VERSION 5.7 ;
  NOWIREEXTENSIONATPIN ON ;
  DIVIDERCHAR "/" ;
  BUSBITCHARS "[]" ;
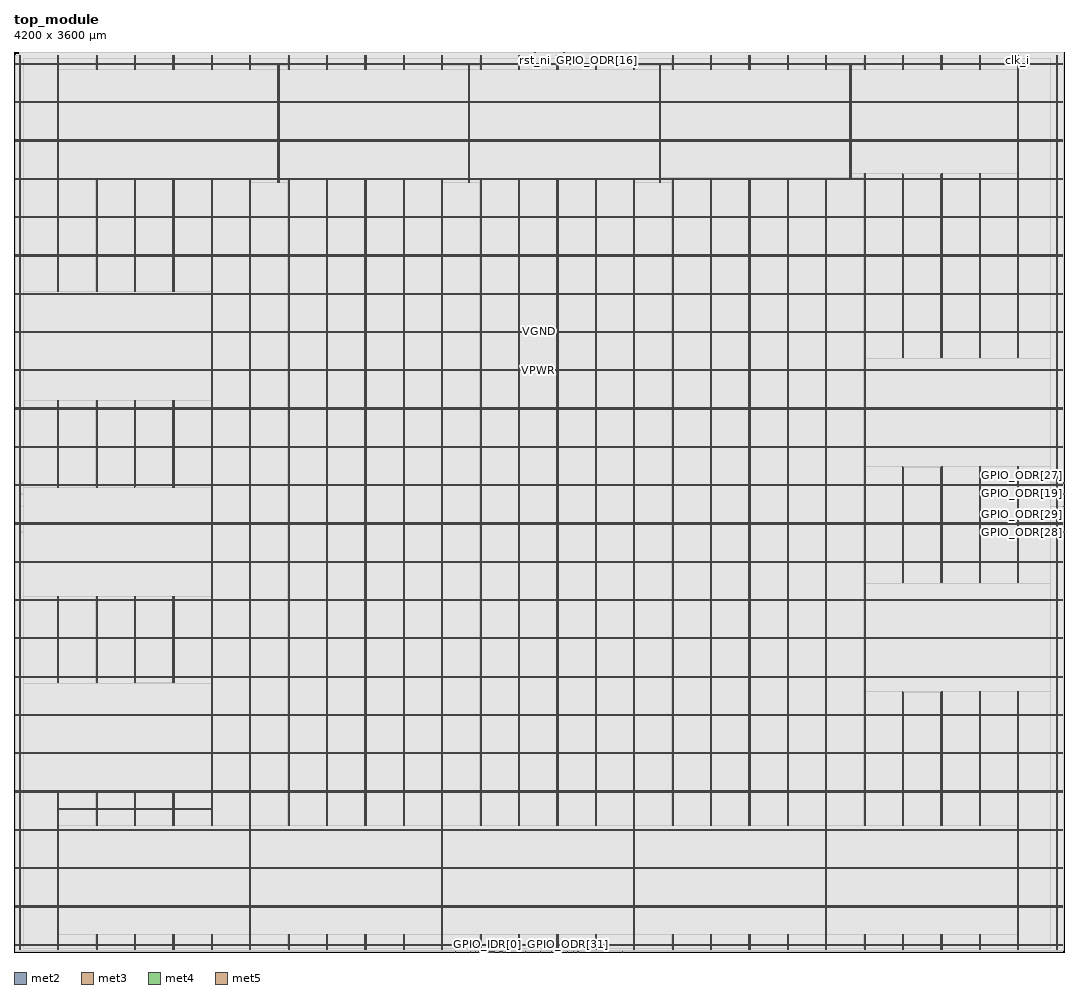
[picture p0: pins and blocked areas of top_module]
MACRO top_module
  CLASS BLOCK ;
  FOREIGN top_module ;
  ORIGIN 0.000 0.000 ;
  SIZE 4200.000 BY 3600.000 ;
  PIN GPIO_IDR[0]
    DIRECTION INPUT ;
    USE SIGNAL ;
    ANTENNAGATEAREA 0.126000 ;
    PORT
      LAYER met2 ;
        RECT 1895.290 0.000 1895.570 0.280 ;
    END
  END GPIO_IDR[0]
  PIN GPIO_IDR[10]
    DIRECTION INPUT ;
    USE SIGNAL ;
    ANTENNAGATEAREA 0.126000 ;
    PORT
      LAYER met2 ;
        RECT 1898.970 0.000 1899.250 0.280 ;
    END
  END GPIO_IDR[10]
  PIN GPIO_IDR[11]
    DIRECTION INPUT ;
    USE SIGNAL ;
    ANTENNAGATEAREA 0.126000 ;
    PORT
      LAYER met2 ;
        RECT 1899.890 0.000 1900.170 0.280 ;
    END
  END GPIO_IDR[11]
  PIN GPIO_IDR[12]
    DIRECTION INPUT ;
    USE SIGNAL ;
    ANTENNAGATEAREA 0.126000 ;
    PORT
      LAYER met2 ;
        RECT 1915.530 0.000 1915.810 0.280 ;
    END
  END GPIO_IDR[12]
  PIN GPIO_IDR[13]
    DIRECTION INPUT ;
    USE SIGNAL ;
    ANTENNAGATEAREA 0.126000 ;
    PORT
      LAYER met2 ;
        RECT 1914.610 0.000 1914.890 0.280 ;
    END
  END GPIO_IDR[13]
  PIN GPIO_IDR[14]
    DIRECTION INPUT ;
    USE SIGNAL ;
    ANTENNAGATEAREA 0.126000 ;
    PORT
      LAYER met2 ;
        RECT 1916.450 0.000 1916.730 0.280 ;
    END
  END GPIO_IDR[14]
  PIN GPIO_IDR[15]
    DIRECTION INPUT ;
    USE SIGNAL ;
    ANTENNAGATEAREA 0.126000 ;
    PORT
      LAYER met2 ;
        RECT 1913.690 0.000 1913.970 0.280 ;
    END
  END GPIO_IDR[15]
  PIN GPIO_IDR[16]
    DIRECTION INPUT ;
    USE SIGNAL ;
    ANTENNAGATEAREA 0.126000 ;
    PORT
      LAYER met2 ;
        RECT 1950.490 0.000 1950.770 0.280 ;
    END
  END GPIO_IDR[16]
  PIN GPIO_IDR[17]
    DIRECTION INPUT ;
    USE SIGNAL ;
    ANTENNAGATEAREA 0.126000 ;
    PORT
      LAYER met2 ;
        RECT 1949.570 0.000 1949.850 0.280 ;
    END
  END GPIO_IDR[17]
  PIN GPIO_IDR[18]
    DIRECTION INPUT ;
    USE SIGNAL ;
    ANTENNAGATEAREA 0.126000 ;
    PORT
      LAYER met2 ;
        RECT 1945.890 0.000 1946.170 0.280 ;
    END
  END GPIO_IDR[18]
  PIN GPIO_IDR[19]
    DIRECTION INPUT ;
    USE SIGNAL ;
    ANTENNAGATEAREA 0.126000 ;
    PORT
      LAYER met2 ;
        RECT 1946.810 0.000 1947.090 0.280 ;
    END
  END GPIO_IDR[19]
  PIN GPIO_IDR[1]
    DIRECTION INPUT ;
    USE SIGNAL ;
    ANTENNAGATEAREA 0.126000 ;
    PORT
      LAYER met2 ;
        RECT 1887.010 0.000 1887.290 0.280 ;
    END
  END GPIO_IDR[1]
  PIN GPIO_IDR[20]
    DIRECTION INPUT ;
    USE SIGNAL ;
    ANTENNAGATEAREA 0.126000 ;
    PORT
      LAYER met2 ;
        RECT 1966.130 0.000 1966.410 0.280 ;
    END
  END GPIO_IDR[20]
  PIN GPIO_IDR[21]
    DIRECTION INPUT ;
    USE SIGNAL ;
    ANTENNAGATEAREA 0.126000 ;
    PORT
      LAYER met2 ;
        RECT 1965.210 0.000 1965.490 0.280 ;
    END
  END GPIO_IDR[21]
  PIN GPIO_IDR[22]
    DIRECTION INPUT ;
    USE SIGNAL ;
    ANTENNAGATEAREA 0.126000 ;
    PORT
      LAYER met2 ;
        RECT 1967.050 0.000 1967.330 0.280 ;
    END
  END GPIO_IDR[22]
  PIN GPIO_IDR[23]
    DIRECTION INPUT ;
    USE SIGNAL ;
    ANTENNAGATEAREA 0.126000 ;
    PORT
      LAYER met2 ;
        RECT 1964.290 0.000 1964.570 0.280 ;
    END
  END GPIO_IDR[23]
  PIN GPIO_IDR[24]
    DIRECTION INPUT ;
    USE SIGNAL ;
    ANTENNAGATEAREA 0.126000 ;
    PORT
      LAYER met2 ;
        RECT 1942.210 0.000 1942.490 0.280 ;
    END
  END GPIO_IDR[24]
  PIN GPIO_IDR[25]
    DIRECTION INPUT ;
    USE SIGNAL ;
    ANTENNAGATEAREA 0.126000 ;
    PORT
      LAYER met2 ;
        RECT 1952.330 0.000 1952.610 0.280 ;
    END
  END GPIO_IDR[25]
  PIN GPIO_IDR[26]
    DIRECTION INPUT ;
    USE SIGNAL ;
    ANTENNAGATEAREA 0.126000 ;
    PORT
      LAYER met2 ;
        RECT 1944.970 0.000 1945.250 0.280 ;
    END
  END GPIO_IDR[26]
  PIN GPIO_IDR[27]
    DIRECTION INPUT ;
    USE SIGNAL ;
    ANTENNAGATEAREA 0.126000 ;
    PORT
      LAYER met2 ;
        RECT 1951.410 0.000 1951.690 0.280 ;
    END
  END GPIO_IDR[27]
  PIN GPIO_IDR[28]
    DIRECTION INPUT ;
    USE SIGNAL ;
    ANTENNAGATEAREA 0.126000 ;
    PORT
      LAYER met2 ;
        RECT 1921.970 0.000 1922.250 0.280 ;
    END
  END GPIO_IDR[28]
  PIN GPIO_IDR[29]
    DIRECTION INPUT ;
    USE SIGNAL ;
    ANTENNAGATEAREA 0.126000 ;
    PORT
      LAYER met2 ;
        RECT 1921.050 0.000 1921.330 0.280 ;
    END
  END GPIO_IDR[29]
  PIN GPIO_IDR[2]
    DIRECTION INPUT ;
    USE SIGNAL ;
    ANTENNAGATEAREA 0.126000 ;
    PORT
      LAYER met2 ;
        RECT 1886.090 0.000 1886.370 0.280 ;
    END
  END GPIO_IDR[2]
  PIN GPIO_IDR[30]
    DIRECTION INPUT ;
    USE SIGNAL ;
    ANTENNAGATEAREA 0.126000 ;
    PORT
      LAYER met2 ;
        RECT 1880.570 0.000 1880.850 0.280 ;
    END
  END GPIO_IDR[30]
  PIN GPIO_IDR[31]
    DIRECTION INPUT ;
    USE SIGNAL ;
    ANTENNAGATEAREA 0.126000 ;
    PORT
      LAYER met2 ;
        RECT 1917.370 0.000 1917.650 0.280 ;
    END
  END GPIO_IDR[31]
  PIN GPIO_IDR[3]
    DIRECTION INPUT ;
    USE SIGNAL ;
    ANTENNAGATEAREA 0.126000 ;
    PORT
      LAYER met2 ;
        RECT 1885.170 0.000 1885.450 0.280 ;
    END
  END GPIO_IDR[3]
  PIN GPIO_IDR[4]
    DIRECTION INPUT ;
    USE SIGNAL ;
    ANTENNAGATEAREA 0.126000 ;
    PORT
      LAYER met2 ;
        RECT 1870.450 0.000 1870.730 0.280 ;
    END
  END GPIO_IDR[4]
  PIN GPIO_IDR[5]
    DIRECTION INPUT ;
    USE SIGNAL ;
    ANTENNAGATEAREA 0.126000 ;
    PORT
      LAYER met2 ;
        RECT 1875.970 0.000 1876.250 0.280 ;
    END
  END GPIO_IDR[5]
  PIN GPIO_IDR[6]
    DIRECTION INPUT ;
    USE SIGNAL ;
    ANTENNAGATEAREA 0.126000 ;
    PORT
      LAYER met2 ;
        RECT 1879.650 0.000 1879.930 0.280 ;
    END
  END GPIO_IDR[6]
  PIN GPIO_IDR[7]
    DIRECTION INPUT ;
    USE SIGNAL ;
    ANTENNAGATEAREA 0.126000 ;
    PORT
      LAYER met2 ;
        RECT 1878.730 0.000 1879.010 0.280 ;
    END
  END GPIO_IDR[7]
  PIN GPIO_IDR[8]
    DIRECTION INPUT ;
    USE SIGNAL ;
    ANTENNAGATEAREA 0.126000 ;
    PORT
      LAYER met2 ;
        RECT 1898.050 0.000 1898.330 0.280 ;
    END
  END GPIO_IDR[8]
  PIN GPIO_IDR[9]
    DIRECTION INPUT ;
    USE SIGNAL ;
    ANTENNAGATEAREA 0.126000 ;
    PORT
      LAYER met2 ;
        RECT 1897.130 0.000 1897.410 0.280 ;
    END
  END GPIO_IDR[9]
  PIN GPIO_ODR[0]
    DIRECTION OUTPUT ;
    USE SIGNAL ;
    ANTENNADIFFAREA 0.340600 ;
    PORT
      LAYER met2 ;
        RECT 1887.930 0.000 1888.210 0.280 ;
    END
  END GPIO_ODR[0]
  PIN GPIO_ODR[10]
    DIRECTION OUTPUT ;
    USE SIGNAL ;
    ANTENNADIFFAREA 0.340600 ;
    PORT
      LAYER met2 ;
        RECT 1900.810 0.000 1901.090 0.280 ;
    END
  END GPIO_ODR[10]
  PIN GPIO_ODR[11]
    DIRECTION OUTPUT ;
    USE SIGNAL ;
    ANTENNADIFFAREA 0.340600 ;
    PORT
      LAYER met2 ;
        RECT 1901.730 0.000 1902.010 0.280 ;
    END
  END GPIO_ODR[11]
  PIN GPIO_ODR[12]
    DIRECTION OUTPUT ;
    USE SIGNAL ;
    ANTENNADIFFAREA 0.340600 ;
    PORT
      LAYER met2 ;
        RECT 1907.250 0.000 1907.530 0.280 ;
    END
  END GPIO_ODR[12]
  PIN GPIO_ODR[13]
    DIRECTION OUTPUT ;
    USE SIGNAL ;
    ANTENNADIFFAREA 0.340600 ;
    PORT
      LAYER met2 ;
        RECT 1910.930 0.000 1911.210 0.280 ;
    END
  END GPIO_ODR[13]
  PIN GPIO_ODR[14]
    DIRECTION OUTPUT ;
    USE SIGNAL ;
    ANTENNADIFFAREA 0.340600 ;
    PORT
      LAYER met2 ;
        RECT 1912.770 0.000 1913.050 0.280 ;
    END
  END GPIO_ODR[14]
  PIN GPIO_ODR[15]
    DIRECTION OUTPUT ;
    USE SIGNAL ;
    ANTENNADIFFAREA 0.340600 ;
    PORT
      LAYER met2 ;
        RECT 1902.650 0.000 1902.930 0.280 ;
    END
  END GPIO_ODR[15]
  PIN GPIO_ODR[16]
    DIRECTION OUTPUT ;
    USE SIGNAL ;
    PORT
      LAYER met2 ;
        RECT 2333.210 3599.720 2333.490 3600.000 ;
    END
  END GPIO_ODR[16]
  PIN GPIO_ODR[17]
    DIRECTION OUTPUT ;
    USE SIGNAL ;
    PORT
      LAYER met2 ;
        RECT 2394.850 3599.720 2395.130 3600.000 ;
    END
  END GPIO_ODR[17]
  PIN GPIO_ODR[18]
    DIRECTION OUTPUT ;
    USE SIGNAL ;
    PORT
      LAYER met2 ;
        RECT 2435.330 0.000 2435.610 0.280 ;
    END
  END GPIO_ODR[18]
  PIN GPIO_ODR[19]
    DIRECTION OUTPUT ;
    USE SIGNAL ;
    PORT
      LAYER met3 ;
        RECT 4199.400 1831.960 4200.000 1832.560 ;
    END
  END GPIO_ODR[19]
  PIN GPIO_ODR[1]
    DIRECTION OUTPUT ;
    USE SIGNAL ;
    ANTENNADIFFAREA 0.340600 ;
    PORT
      LAYER met2 ;
        RECT 1888.850 0.000 1889.130 0.280 ;
    END
  END GPIO_ODR[1]
  PIN GPIO_ODR[20]
    DIRECTION OUTPUT ;
    USE SIGNAL ;
    PORT
      LAYER met2 ;
        RECT 2220.970 3599.720 2221.250 3600.000 ;
    END
  END GPIO_ODR[20]
  PIN GPIO_ODR[21]
    DIRECTION OUTPUT ;
    USE SIGNAL ;
    PORT
      LAYER met2 ;
        RECT 2192.450 3599.720 2192.730 3600.000 ;
    END
  END GPIO_ODR[21]
  PIN GPIO_ODR[22]
    DIRECTION OUTPUT ;
    USE SIGNAL ;
    PORT
      LAYER met2 ;
        RECT 2144.610 3599.720 2144.890 3600.000 ;
    END
  END GPIO_ODR[22]
  PIN GPIO_ODR[23]
    DIRECTION OUTPUT ;
    USE SIGNAL ;
    PORT
      LAYER met2 ;
        RECT 2199.810 3599.720 2200.090 3600.000 ;
    END
  END GPIO_ODR[23]
  PIN GPIO_ODR[24]
    DIRECTION OUTPUT ;
    USE SIGNAL ;
    PORT
      LAYER met2 ;
        RECT 2320.330 3599.720 2320.610 3600.000 ;
    END
  END GPIO_ODR[24]
  PIN GPIO_ODR[25]
    DIRECTION OUTPUT ;
    USE SIGNAL ;
    PORT
      LAYER met2 ;
        RECT 2295.490 3599.720 2295.770 3600.000 ;
    END
  END GPIO_ODR[25]
  PIN GPIO_ODR[26]
    DIRECTION OUTPUT ;
    USE SIGNAL ;
    PORT
      LAYER met2 ;
        RECT 2405.890 3599.720 2406.170 3600.000 ;
    END
  END GPIO_ODR[26]
  PIN GPIO_ODR[27]
    DIRECTION OUTPUT ;
    USE SIGNAL ;
    PORT
      LAYER met3 ;
        RECT 4199.400 1875.480 4200.000 1876.080 ;
    END
  END GPIO_ODR[27]
  PIN GPIO_ODR[28]
    DIRECTION OUTPUT ;
    USE SIGNAL ;
    PORT
      LAYER met3 ;
        RECT 4199.400 1679.640 4200.000 1680.240 ;
    END
  END GPIO_ODR[28]
  PIN GPIO_ODR[29]
    DIRECTION OUTPUT ;
    USE SIGNAL ;
    PORT
      LAYER met3 ;
        RECT 4199.400 1781.640 4200.000 1782.240 ;
    END
  END GPIO_ODR[29]
  PIN GPIO_ODR[2]
    DIRECTION OUTPUT ;
    USE SIGNAL ;
    ANTENNADIFFAREA 0.340600 ;
    PORT
      LAYER met2 ;
        RECT 1889.770 0.000 1890.050 0.280 ;
    END
  END GPIO_ODR[2]
  PIN GPIO_ODR[30]
    DIRECTION OUTPUT ;
    USE SIGNAL ;
    PORT
      LAYER met2 ;
        RECT 2297.330 3599.720 2297.610 3600.000 ;
    END
  END GPIO_ODR[30]
  PIN GPIO_ODR[31]
    DIRECTION OUTPUT ;
    USE SIGNAL ;
    PORT
      LAYER met2 ;
        RECT 2214.530 0.000 2214.810 0.280 ;
    END
  END GPIO_ODR[31]
  PIN GPIO_ODR[3]
    DIRECTION OUTPUT ;
    USE SIGNAL ;
    ANTENNADIFFAREA 0.340600 ;
    PORT
      LAYER met2 ;
        RECT 1882.410 0.000 1882.690 0.280 ;
    END
  END GPIO_ODR[3]
  PIN GPIO_ODR[4]
    DIRECTION OUTPUT ;
    USE SIGNAL ;
    ANTENNADIFFAREA 0.340600 ;
    PORT
      LAYER met2 ;
        RECT 1866.770 0.000 1867.050 0.280 ;
    END
  END GPIO_ODR[4]
  PIN GPIO_ODR[5]
    DIRECTION OUTPUT ;
    USE SIGNAL ;
    ANTENNADIFFAREA 0.340600 ;
    PORT
      LAYER met2 ;
        RECT 1874.130 0.000 1874.410 0.280 ;
    END
  END GPIO_ODR[5]
  PIN GPIO_ODR[6]
    DIRECTION OUTPUT ;
    USE SIGNAL ;
    ANTENNADIFFAREA 0.340600 ;
    PORT
      LAYER met2 ;
        RECT 1881.490 0.000 1881.770 0.280 ;
    END
  END GPIO_ODR[6]
  PIN GPIO_ODR[7]
    DIRECTION OUTPUT ;
    USE SIGNAL ;
    ANTENNADIFFAREA 0.340600 ;
    PORT
      LAYER met2 ;
        RECT 1891.610 0.000 1891.890 0.280 ;
    END
  END GPIO_ODR[7]
  PIN GPIO_ODR[8]
    DIRECTION OUTPUT ;
    USE SIGNAL ;
    ANTENNADIFFAREA 0.340600 ;
    PORT
      LAYER met2 ;
        RECT 1893.450 0.000 1893.730 0.280 ;
    END
  END GPIO_ODR[8]
  PIN GPIO_ODR[9]
    DIRECTION OUTPUT ;
    USE SIGNAL ;
    ANTENNADIFFAREA 0.340600 ;
    PORT
      LAYER met2 ;
        RECT 1892.530 0.000 1892.810 0.280 ;
    END
  END GPIO_ODR[9]
  PIN I2C_SCL
    DIRECTION OUTPUT ;
    USE SIGNAL ;
    ANTENNADIFFAREA 0.340600 ;
    PORT
      LAYER met2 ;
        RECT 2105.970 0.000 2106.250 0.280 ;
    END
  END I2C_SCL
  PIN I2C_SDA
    DIRECTION INOUT ;
    USE SIGNAL ;
    ANTENNAGATEAREA 0.126000 ;
    ANTENNADIFFAREA 1.782000 ;
    PORT
      LAYER met2 ;
        RECT 2046.170 0.000 2046.450 0.280 ;
    END
  END I2C_SDA
  PIN QSPI_CS
    DIRECTION OUTPUT ;
    USE SIGNAL ;
    ANTENNADIFFAREA 0.340600 ;
    PORT
      LAYER met2 ;
        RECT 2156.570 0.000 2156.850 0.280 ;
    END
  END QSPI_CS
  PIN QSPI_IO0
    DIRECTION INOUT ;
    USE SIGNAL ;
    ANTENNAGATEAREA 0.990000 ;
    ANTENNADIFFAREA 1.782000 ;
    PORT
      LAYER met2 ;
        RECT 2238.450 0.000 2238.730 0.280 ;
    END
  END QSPI_IO0
  PIN QSPI_IO1
    DIRECTION INOUT ;
    USE SIGNAL ;
    ANTENNAGATEAREA 0.990000 ;
    ANTENNADIFFAREA 1.782000 ;
    PORT
      LAYER met2 ;
        RECT 2255.010 0.000 2255.290 0.280 ;
    END
  END QSPI_IO1
  PIN QSPI_IO2
    DIRECTION INOUT ;
    USE SIGNAL ;
    ANTENNAGATEAREA 0.990000 ;
    ANTENNADIFFAREA 1.782000 ;
    PORT
      LAYER met2 ;
        RECT 2255.930 0.000 2256.210 0.280 ;
    END
  END QSPI_IO2
  PIN QSPI_IO3
    DIRECTION INOUT ;
    USE SIGNAL ;
    ANTENNAGATEAREA 0.990000 ;
    ANTENNADIFFAREA 1.782000 ;
    PORT
      LAYER met2 ;
        RECT 2256.850 0.000 2257.130 0.280 ;
    END
  END QSPI_IO3
  PIN QSPI_SCLK
    DIRECTION OUTPUT ;
    USE SIGNAL ;
    ANTENNADIFFAREA 0.340600 ;
    PORT
      LAYER met2 ;
        RECT 2149.210 0.000 2149.490 0.280 ;
    END
  END QSPI_SCLK
  PIN UART_GU_RX
    DIRECTION INPUT ;
    USE SIGNAL ;
    ANTENNAGATEAREA 0.126000 ;
    PORT
      LAYER met2 ;
        RECT 1869.530 0.000 1869.810 0.280 ;
    END
  END UART_GU_RX
  PIN UART_GU_TX
    DIRECTION OUTPUT ;
    USE SIGNAL ;
    ANTENNADIFFAREA 0.340600 ;
    PORT
      LAYER met2 ;
        RECT 1844.690 0.000 1844.970 0.280 ;
    END
  END UART_GU_TX
  PIN UART_YZ_RX
    DIRECTION INPUT ;
    USE SIGNAL ;
    ANTENNAGATEAREA 0.126000 ;
    PORT
      LAYER met2 ;
        RECT 1767.410 0.000 1767.690 0.280 ;
    END
  END UART_YZ_RX
  PIN UART_YZ_TX
    DIRECTION OUTPUT ;
    USE SIGNAL ;
    ANTENNADIFFAREA 0.340600 ;
    PORT
      LAYER met2 ;
        RECT 1826.290 0.000 1826.570 0.280 ;
    END
  END UART_YZ_TX
  PIN VGND
    DIRECTION INOUT ;
    USE GROUND ;
    PORT
      LAYER met4 ;
        RECT 24.340 10.640 25.940 3587.920 ;
    END
    PORT
      LAYER met4 ;
        RECT 177.940 10.640 179.540 639.400 ;
    END
    PORT
      LAYER met4 ;
        RECT 177.940 1076.220 179.540 1422.500 ;
    END
    PORT
      LAYER met4 ;
        RECT 177.940 1859.320 179.540 2205.600 ;
    END
    PORT
      LAYER met4 ;
        RECT 177.940 2642.420 179.540 3587.920 ;
    END
    PORT
      LAYER met4 ;
        RECT 331.540 10.640 333.140 70.320 ;
    END
    PORT
      LAYER met4 ;
        RECT 331.540 506.220 333.140 640.320 ;
    END
    PORT
      LAYER met4 ;
        RECT 331.540 1076.220 333.140 1423.420 ;
    END
    PORT
      LAYER met4 ;
        RECT 331.540 1859.320 333.140 2206.520 ;
    END
    PORT
      LAYER met4 ;
        RECT 331.540 2642.420 333.140 3093.780 ;
    END
    PORT
      LAYER met4 ;
        RECT 331.540 3529.680 333.140 3587.920 ;
    END
    PORT
      LAYER met4 ;
        RECT 485.140 10.640 486.740 69.400 ;
    END
    PORT
      LAYER met4 ;
        RECT 485.140 506.220 486.740 639.400 ;
    END
    PORT
      LAYER met4 ;
        RECT 485.140 1077.140 486.740 1422.500 ;
    END
    PORT
      LAYER met4 ;
        RECT 485.140 1860.240 486.740 2205.600 ;
    END
    PORT
      LAYER met4 ;
        RECT 485.140 2643.340 486.740 3092.860 ;
    END
    PORT
      LAYER met4 ;
        RECT 485.140 3529.680 486.740 3587.920 ;
    END
    PORT
      LAYER met4 ;
        RECT 638.740 10.640 640.340 70.320 ;
    END
    PORT
      LAYER met4 ;
        RECT 638.740 506.220 640.340 640.320 ;
    END
    PORT
      LAYER met4 ;
        RECT 638.740 1076.220 640.340 1423.420 ;
    END
    PORT
      LAYER met4 ;
        RECT 638.740 1859.320 640.340 2206.520 ;
    END
    PORT
      LAYER met4 ;
        RECT 638.740 2642.420 640.340 3092.860 ;
    END
    PORT
      LAYER met4 ;
        RECT 638.740 3530.600 640.340 3587.920 ;
    END
    PORT
      LAYER met4 ;
        RECT 792.340 10.640 793.940 70.320 ;
    END
    PORT
      LAYER met4 ;
        RECT 792.340 506.220 793.940 3093.780 ;
    END
    PORT
      LAYER met4 ;
        RECT 792.340 3529.680 793.940 3587.920 ;
    END
    PORT
      LAYER met4 ;
        RECT 945.940 10.640 947.540 3093.780 ;
    END
    PORT
      LAYER met4 ;
        RECT 945.940 3529.680 947.540 3587.920 ;
    END
    PORT
      LAYER met4 ;
        RECT 1099.540 10.640 1101.140 70.320 ;
    END
    PORT
      LAYER met4 ;
        RECT 1099.540 506.220 1101.140 3093.780 ;
    END
    PORT
      LAYER met4 ;
        RECT 1099.540 3529.680 1101.140 3587.920 ;
    END
    PORT
      LAYER met4 ;
        RECT 1253.140 10.640 1254.740 70.320 ;
    END
    PORT
      LAYER met4 ;
        RECT 1253.140 506.220 1254.740 3092.860 ;
    END
    PORT
      LAYER met4 ;
        RECT 1253.140 3529.680 1254.740 3587.920 ;
    END
    PORT
      LAYER met4 ;
        RECT 1406.740 10.640 1408.340 70.320 ;
    END
    PORT
      LAYER met4 ;
        RECT 1406.740 506.220 1408.340 3093.780 ;
    END
    PORT
      LAYER met4 ;
        RECT 1406.740 3529.680 1408.340 3587.920 ;
    END
    PORT
      LAYER met4 ;
        RECT 1560.340 10.640 1561.940 70.320 ;
    END
    PORT
      LAYER met4 ;
        RECT 1560.340 506.220 1561.940 3093.780 ;
    END
    PORT
      LAYER met4 ;
        RECT 1560.340 3529.680 1561.940 3587.920 ;
    END
    PORT
      LAYER met4 ;
        RECT 1713.940 10.640 1715.540 3092.860 ;
    END
    PORT
      LAYER met4 ;
        RECT 1713.940 3529.680 1715.540 3587.920 ;
    END
    PORT
      LAYER met4 ;
        RECT 1867.540 10.640 1869.140 69.400 ;
    END
    PORT
      LAYER met4 ;
        RECT 1867.540 506.220 1869.140 3093.780 ;
    END
    PORT
      LAYER met4 ;
        RECT 1867.540 3529.680 1869.140 3587.920 ;
    END
    PORT
      LAYER met4 ;
        RECT 2021.140 10.640 2022.740 70.320 ;
    END
    PORT
      LAYER met4 ;
        RECT 2021.140 506.220 2022.740 3092.860 ;
    END
    PORT
      LAYER met4 ;
        RECT 2021.140 3529.680 2022.740 3587.920 ;
    END
    PORT
      LAYER met4 ;
        RECT 2174.740 10.640 2176.340 69.400 ;
    END
    PORT
      LAYER met4 ;
        RECT 2174.740 507.140 2176.340 3093.780 ;
    END
    PORT
      LAYER met4 ;
        RECT 2174.740 3529.680 2176.340 3587.920 ;
    END
    PORT
      LAYER met4 ;
        RECT 2328.340 10.640 2329.940 70.320 ;
    END
    PORT
      LAYER met4 ;
        RECT 2328.340 506.220 2329.940 3093.780 ;
    END
    PORT
      LAYER met4 ;
        RECT 2328.340 3530.600 2329.940 3587.920 ;
    END
    PORT
      LAYER met4 ;
        RECT 2481.940 10.640 2483.540 3093.780 ;
    END
    PORT
      LAYER met4 ;
        RECT 2481.940 3529.680 2483.540 3587.920 ;
    END
    PORT
      LAYER met4 ;
        RECT 2635.540 10.640 2637.140 69.400 ;
    END
    PORT
      LAYER met4 ;
        RECT 2635.540 506.220 2637.140 3093.780 ;
    END
    PORT
      LAYER met4 ;
        RECT 2635.540 3529.680 2637.140 3587.920 ;
    END
    PORT
      LAYER met4 ;
        RECT 2789.140 10.640 2790.740 69.400 ;
    END
    PORT
      LAYER met4 ;
        RECT 2789.140 507.140 2790.740 3092.860 ;
    END
    PORT
      LAYER met4 ;
        RECT 2789.140 3530.600 2790.740 3587.920 ;
    END
    PORT
      LAYER met4 ;
        RECT 2942.740 10.640 2944.340 70.320 ;
    END
    PORT
      LAYER met4 ;
        RECT 2942.740 506.220 2944.340 3093.780 ;
    END
    PORT
      LAYER met4 ;
        RECT 2942.740 3529.680 2944.340 3587.920 ;
    END
    PORT
      LAYER met4 ;
        RECT 3096.340 10.640 3097.940 70.320 ;
    END
    PORT
      LAYER met4 ;
        RECT 3096.340 506.220 3097.940 3093.780 ;
    END
    PORT
      LAYER met4 ;
        RECT 3096.340 3529.680 3097.940 3587.920 ;
    END
    PORT
      LAYER met4 ;
        RECT 3249.940 10.640 3251.540 3093.780 ;
    END
    PORT
      LAYER met4 ;
        RECT 3249.940 3529.680 3251.540 3587.920 ;
    END
    PORT
      LAYER met4 ;
        RECT 3403.540 10.640 3405.140 69.400 ;
    END
    PORT
      LAYER met4 ;
        RECT 3403.540 506.220 3405.140 3112.820 ;
    END
    PORT
      LAYER met4 ;
        RECT 3403.540 3529.680 3405.140 3587.920 ;
    END
    PORT
      LAYER met4 ;
        RECT 3557.140 10.640 3558.740 69.400 ;
    END
    PORT
      LAYER met4 ;
        RECT 3557.140 506.220 3558.740 1039.400 ;
    END
    PORT
      LAYER met4 ;
        RECT 3557.140 1476.220 3558.740 1939.400 ;
    END
    PORT
      LAYER met4 ;
        RECT 3557.140 2376.220 3558.740 3111.900 ;
    END
    PORT
      LAYER met4 ;
        RECT 3557.140 3530.600 3558.740 3587.920 ;
    END
    PORT
      LAYER met4 ;
        RECT 3710.740 10.640 3712.340 70.320 ;
    END
    PORT
      LAYER met4 ;
        RECT 3710.740 506.220 3712.340 1040.320 ;
    END
    PORT
      LAYER met4 ;
        RECT 3710.740 1476.220 3712.340 1940.320 ;
    END
    PORT
      LAYER met4 ;
        RECT 3710.740 2376.220 3712.340 3112.820 ;
    END
    PORT
      LAYER met4 ;
        RECT 3710.740 3529.680 3712.340 3587.920 ;
    END
    PORT
      LAYER met4 ;
        RECT 3864.340 10.640 3865.940 70.320 ;
    END
    PORT
      LAYER met4 ;
        RECT 3864.340 506.220 3865.940 1040.320 ;
    END
    PORT
      LAYER met4 ;
        RECT 3864.340 1476.220 3865.940 1940.320 ;
    END
    PORT
      LAYER met4 ;
        RECT 3864.340 2376.220 3865.940 3112.820 ;
    END
    PORT
      LAYER met4 ;
        RECT 3864.340 3529.680 3865.940 3587.920 ;
    END
    PORT
      LAYER met4 ;
        RECT 4017.940 10.640 4019.540 1040.320 ;
    END
    PORT
      LAYER met4 ;
        RECT 4017.940 1476.220 4019.540 1940.320 ;
    END
    PORT
      LAYER met4 ;
        RECT 4017.940 2376.220 4019.540 3587.920 ;
    END
    PORT
      LAYER met4 ;
        RECT 4171.540 10.640 4173.140 3587.920 ;
    END
    PORT
      LAYER met5 ;
        RECT 5.520 30.030 4194.280 31.630 ;
    END
    PORT
      LAYER met5 ;
        RECT 5.520 183.210 4194.280 184.810 ;
    END
    PORT
      LAYER met5 ;
        RECT 5.520 336.390 4194.280 337.990 ;
    END
    PORT
      LAYER met5 ;
        RECT 5.520 489.570 4194.280 491.170 ;
    END
    PORT
      LAYER met5 ;
        RECT 5.520 642.750 4194.280 644.350 ;
    END
    PORT
      LAYER met5 ;
        RECT 5.520 795.930 4194.280 797.530 ;
    END
    PORT
      LAYER met5 ;
        RECT 5.520 949.110 4194.280 950.710 ;
    END
    PORT
      LAYER met5 ;
        RECT 5.520 1102.290 4194.280 1103.890 ;
    END
    PORT
      LAYER met5 ;
        RECT 5.520 1255.470 4194.280 1257.070 ;
    END
    PORT
      LAYER met5 ;
        RECT 5.520 1408.650 4194.280 1410.250 ;
    END
    PORT
      LAYER met5 ;
        RECT 5.520 1561.830 4194.280 1563.430 ;
    END
    PORT
      LAYER met5 ;
        RECT 5.520 1715.010 4194.280 1716.610 ;
    END
    PORT
      LAYER met5 ;
        RECT 5.520 1868.190 4194.280 1869.790 ;
    END
    PORT
      LAYER met5 ;
        RECT 5.520 2021.370 4194.280 2022.970 ;
    END
    PORT
      LAYER met5 ;
        RECT 5.520 2174.550 4194.280 2176.150 ;
    END
    PORT
      LAYER met5 ;
        RECT 5.520 2327.730 4194.280 2329.330 ;
    END
    PORT
      LAYER met5 ;
        RECT 5.520 2480.910 4194.280 2482.510 ;
    END
    PORT
      LAYER met5 ;
        RECT 5.520 2634.090 4194.280 2635.690 ;
    END
    PORT
      LAYER met5 ;
        RECT 5.520 2787.270 4194.280 2788.870 ;
    END
    PORT
      LAYER met5 ;
        RECT 5.520 2940.450 4194.280 2942.050 ;
    END
    PORT
      LAYER met5 ;
        RECT 5.520 3093.630 4194.280 3095.230 ;
    END
    PORT
      LAYER met5 ;
        RECT 5.520 3246.810 4194.280 3248.410 ;
    END
    PORT
      LAYER met5 ;
        RECT 5.520 3399.990 4194.280 3401.590 ;
    END
    PORT
      LAYER met5 ;
        RECT 5.520 3553.170 4194.280 3554.770 ;
    END
    PORT
      LAYER met4 ;
        RECT 1058.580 3078.800 1060.180 3544.400 ;
    END
    PORT
      LAYER met5 ;
        RECT 174.640 572.100 793.940 573.700 ;
    END
    PORT
      LAYER met4 ;
        RECT 1821.260 3078.800 1822.860 3544.400 ;
    END
    PORT
      LAYER met4 ;
        RECT 2584.860 3078.800 2586.460 3544.400 ;
    END
    PORT
      LAYER met4 ;
        RECT 3347.540 3097.840 3349.140 3544.400 ;
    END
  END VGND
  PIN VPWR
    DIRECTION INOUT ;
    USE POWER ;
    PORT
      LAYER met4 ;
        RECT 21.040 10.640 22.640 3587.920 ;
    END
    PORT
      LAYER met4 ;
        RECT 174.640 10.640 176.240 640.320 ;
    END
    PORT
      LAYER met4 ;
        RECT 174.640 1076.220 176.240 1423.420 ;
    END
    PORT
      LAYER met4 ;
        RECT 174.640 1859.320 176.240 2206.520 ;
    END
    PORT
      LAYER met4 ;
        RECT 174.640 2642.420 176.240 3587.920 ;
    END
    PORT
      LAYER met4 ;
        RECT 328.240 10.640 329.840 69.400 ;
    END
    PORT
      LAYER met4 ;
        RECT 328.240 506.220 329.840 639.400 ;
    END
    PORT
      LAYER met4 ;
        RECT 328.240 1076.220 329.840 1422.500 ;
    END
    PORT
      LAYER met4 ;
        RECT 328.240 1859.320 329.840 2205.600 ;
    END
    PORT
      LAYER met4 ;
        RECT 328.240 2642.420 329.840 3093.780 ;
    END
    PORT
      LAYER met4 ;
        RECT 328.240 3529.680 329.840 3587.920 ;
    END
    PORT
      LAYER met4 ;
        RECT 481.840 10.640 483.440 69.400 ;
    END
    PORT
      LAYER met4 ;
        RECT 481.840 506.220 483.440 640.320 ;
    END
    PORT
      LAYER met4 ;
        RECT 481.840 1076.220 483.440 1423.420 ;
    END
    PORT
      LAYER met4 ;
        RECT 481.840 1859.320 483.440 2206.520 ;
    END
    PORT
      LAYER met4 ;
        RECT 481.840 2642.420 483.440 3093.780 ;
    END
    PORT
      LAYER met4 ;
        RECT 481.840 3529.680 483.440 3587.920 ;
    END
    PORT
      LAYER met4 ;
        RECT 635.440 10.640 637.040 69.400 ;
    END
    PORT
      LAYER met4 ;
        RECT 635.440 507.140 637.040 640.320 ;
    END
    PORT
      LAYER met4 ;
        RECT 635.440 1076.220 637.040 1423.420 ;
    END
    PORT
      LAYER met4 ;
        RECT 635.440 1859.320 637.040 2206.520 ;
    END
    PORT
      LAYER met4 ;
        RECT 635.440 2642.420 637.040 3093.780 ;
    END
    PORT
      LAYER met4 ;
        RECT 635.440 3529.680 637.040 3587.920 ;
    END
    PORT
      LAYER met4 ;
        RECT 789.040 10.640 790.640 70.320 ;
    END
    PORT
      LAYER met4 ;
        RECT 789.040 506.220 790.640 3092.860 ;
    END
    PORT
      LAYER met4 ;
        RECT 789.040 3530.600 790.640 3587.920 ;
    END
    PORT
      LAYER met4 ;
        RECT 942.640 10.640 944.240 3093.780 ;
    END
    PORT
      LAYER met4 ;
        RECT 942.640 3529.680 944.240 3587.920 ;
    END
    PORT
      LAYER met4 ;
        RECT 1096.240 10.640 1097.840 69.400 ;
    END
    PORT
      LAYER met4 ;
        RECT 1096.240 506.220 1097.840 3093.780 ;
    END
    PORT
      LAYER met4 ;
        RECT 1096.240 3529.680 1097.840 3587.920 ;
    END
    PORT
      LAYER met4 ;
        RECT 1249.840 10.640 1251.440 69.400 ;
    END
    PORT
      LAYER met4 ;
        RECT 1249.840 507.140 1251.440 3092.860 ;
    END
    PORT
      LAYER met4 ;
        RECT 1249.840 3529.680 1251.440 3587.920 ;
    END
    PORT
      LAYER met4 ;
        RECT 1403.440 10.640 1405.040 70.320 ;
    END
    PORT
      LAYER met4 ;
        RECT 1403.440 506.220 1405.040 3093.780 ;
    END
    PORT
      LAYER met4 ;
        RECT 1403.440 3529.680 1405.040 3587.920 ;
    END
    PORT
      LAYER met4 ;
        RECT 1557.040 10.640 1558.640 70.320 ;
    END
    PORT
      LAYER met4 ;
        RECT 1557.040 506.220 1558.640 3093.780 ;
    END
    PORT
      LAYER met4 ;
        RECT 1557.040 3529.680 1558.640 3587.920 ;
    END
    PORT
      LAYER met4 ;
        RECT 1710.640 10.640 1712.240 3093.780 ;
    END
    PORT
      LAYER met4 ;
        RECT 1710.640 3529.680 1712.240 3587.920 ;
    END
    PORT
      LAYER met4 ;
        RECT 1864.240 10.640 1865.840 70.320 ;
    END
    PORT
      LAYER met4 ;
        RECT 1864.240 506.220 1865.840 3093.780 ;
    END
    PORT
      LAYER met4 ;
        RECT 1864.240 3529.680 1865.840 3587.920 ;
    END
    PORT
      LAYER met4 ;
        RECT 2017.840 10.640 2019.440 69.400 ;
    END
    PORT
      LAYER met4 ;
        RECT 2017.840 506.220 2019.440 3093.780 ;
    END
    PORT
      LAYER met4 ;
        RECT 2017.840 3529.680 2019.440 3587.920 ;
    END
    PORT
      LAYER met4 ;
        RECT 2171.440 10.640 2173.040 70.320 ;
    END
    PORT
      LAYER met4 ;
        RECT 2171.440 506.220 2173.040 3093.780 ;
    END
    PORT
      LAYER met4 ;
        RECT 2171.440 3529.680 2173.040 3587.920 ;
    END
    PORT
      LAYER met4 ;
        RECT 2325.040 10.640 2326.640 70.320 ;
    END
    PORT
      LAYER met4 ;
        RECT 2325.040 506.220 2326.640 3093.780 ;
    END
    PORT
      LAYER met4 ;
        RECT 2325.040 3529.680 2326.640 3587.920 ;
    END
    PORT
      LAYER met4 ;
        RECT 2478.640 10.640 2480.240 3093.780 ;
    END
    PORT
      LAYER met4 ;
        RECT 2478.640 3529.680 2480.240 3587.920 ;
    END
    PORT
      LAYER met4 ;
        RECT 2632.240 10.640 2633.840 70.320 ;
    END
    PORT
      LAYER met4 ;
        RECT 2632.240 506.220 2633.840 3093.780 ;
    END
    PORT
      LAYER met4 ;
        RECT 2632.240 3529.680 2633.840 3587.920 ;
    END
    PORT
      LAYER met4 ;
        RECT 2785.840 10.640 2787.440 70.320 ;
    END
    PORT
      LAYER met4 ;
        RECT 2785.840 506.220 2787.440 3092.860 ;
    END
    PORT
      LAYER met4 ;
        RECT 2785.840 3529.680 2787.440 3587.920 ;
    END
    PORT
      LAYER met4 ;
        RECT 2939.440 10.640 2941.040 69.400 ;
    END
    PORT
      LAYER met4 ;
        RECT 2939.440 507.140 2941.040 3092.860 ;
    END
    PORT
      LAYER met4 ;
        RECT 2939.440 3530.600 2941.040 3587.920 ;
    END
    PORT
      LAYER met4 ;
        RECT 3093.040 10.640 3094.640 70.320 ;
    END
    PORT
      LAYER met4 ;
        RECT 3093.040 506.220 3094.640 3093.780 ;
    END
    PORT
      LAYER met4 ;
        RECT 3093.040 3529.680 3094.640 3587.920 ;
    END
    PORT
      LAYER met4 ;
        RECT 3246.640 10.640 3248.240 3093.780 ;
    END
    PORT
      LAYER met4 ;
        RECT 3246.640 3529.680 3248.240 3587.920 ;
    END
    PORT
      LAYER met4 ;
        RECT 3400.240 10.640 3401.840 69.400 ;
    END
    PORT
      LAYER met4 ;
        RECT 3400.240 506.220 3401.840 3112.820 ;
    END
    PORT
      LAYER met4 ;
        RECT 3400.240 3529.680 3401.840 3587.920 ;
    END
    PORT
      LAYER met4 ;
        RECT 3553.840 10.640 3555.440 70.320 ;
    END
    PORT
      LAYER met4 ;
        RECT 3553.840 506.220 3555.440 1040.320 ;
    END
    PORT
      LAYER met4 ;
        RECT 3553.840 1476.220 3555.440 1940.320 ;
    END
    PORT
      LAYER met4 ;
        RECT 3553.840 2376.220 3555.440 3112.820 ;
    END
    PORT
      LAYER met4 ;
        RECT 3553.840 3529.680 3555.440 3587.920 ;
    END
    PORT
      LAYER met4 ;
        RECT 3707.440 10.640 3709.040 70.320 ;
    END
    PORT
      LAYER met4 ;
        RECT 3707.440 506.220 3709.040 1039.400 ;
    END
    PORT
      LAYER met4 ;
        RECT 3707.440 1476.220 3709.040 1939.400 ;
    END
    PORT
      LAYER met4 ;
        RECT 3707.440 2376.220 3709.040 3111.900 ;
    END
    PORT
      LAYER met4 ;
        RECT 3707.440 3530.600 3709.040 3587.920 ;
    END
    PORT
      LAYER met4 ;
        RECT 3861.040 10.640 3862.640 70.320 ;
    END
    PORT
      LAYER met4 ;
        RECT 3861.040 506.220 3862.640 1040.320 ;
    END
    PORT
      LAYER met4 ;
        RECT 3861.040 1476.220 3862.640 1940.320 ;
    END
    PORT
      LAYER met4 ;
        RECT 3861.040 2376.220 3862.640 3112.820 ;
    END
    PORT
      LAYER met4 ;
        RECT 3861.040 3529.680 3862.640 3587.920 ;
    END
    PORT
      LAYER met4 ;
        RECT 4014.640 10.640 4016.240 1040.320 ;
    END
    PORT
      LAYER met4 ;
        RECT 4014.640 1476.220 4016.240 1940.320 ;
    END
    PORT
      LAYER met4 ;
        RECT 4014.640 2376.220 4016.240 3587.920 ;
    END
    PORT
      LAYER met4 ;
        RECT 4168.240 10.640 4169.840 3587.920 ;
    END
    PORT
      LAYER met5 ;
        RECT 5.520 26.730 4194.280 28.330 ;
    END
    PORT
      LAYER met5 ;
        RECT 5.520 179.910 4194.280 181.510 ;
    END
    PORT
      LAYER met5 ;
        RECT 5.520 333.090 4194.280 334.690 ;
    END
    PORT
      LAYER met5 ;
        RECT 5.520 486.270 4194.280 487.870 ;
    END
    PORT
      LAYER met5 ;
        RECT 5.520 639.450 4194.280 641.050 ;
    END
    PORT
      LAYER met5 ;
        RECT 5.520 792.630 4194.280 794.230 ;
    END
    PORT
      LAYER met5 ;
        RECT 5.520 945.810 4194.280 947.410 ;
    END
    PORT
      LAYER met5 ;
        RECT 5.520 1098.990 4194.280 1100.590 ;
    END
    PORT
      LAYER met5 ;
        RECT 5.520 1252.170 4194.280 1253.770 ;
    END
    PORT
      LAYER met5 ;
        RECT 5.520 1405.350 4194.280 1406.950 ;
    END
    PORT
      LAYER met5 ;
        RECT 5.520 1558.530 4194.280 1560.130 ;
    END
    PORT
      LAYER met5 ;
        RECT 5.520 1711.710 4194.280 1713.310 ;
    END
    PORT
      LAYER met5 ;
        RECT 5.520 1864.890 4194.280 1866.490 ;
    END
    PORT
      LAYER met5 ;
        RECT 5.520 2018.070 4194.280 2019.670 ;
    END
    PORT
      LAYER met5 ;
        RECT 5.520 2171.250 4194.280 2172.850 ;
    END
    PORT
      LAYER met5 ;
        RECT 5.520 2324.430 4194.280 2326.030 ;
    END
    PORT
      LAYER met5 ;
        RECT 5.520 2477.610 4194.280 2479.210 ;
    END
    PORT
      LAYER met5 ;
        RECT 5.520 2630.790 4194.280 2632.390 ;
    END
    PORT
      LAYER met5 ;
        RECT 5.520 2783.970 4194.280 2785.570 ;
    END
    PORT
      LAYER met5 ;
        RECT 5.520 2937.150 4194.280 2938.750 ;
    END
    PORT
      LAYER met5 ;
        RECT 5.520 3090.330 4194.280 3091.930 ;
    END
    PORT
      LAYER met5 ;
        RECT 5.520 3243.510 4194.280 3245.110 ;
    END
    PORT
      LAYER met5 ;
        RECT 5.520 3396.690 4194.280 3398.290 ;
    END
    PORT
      LAYER met5 ;
        RECT 5.520 3549.870 4194.280 3551.470 ;
    END
    PORT
      LAYER met4 ;
        RECT 1054.900 3078.800 1056.500 3544.400 ;
    END
    PORT
      LAYER met5 ;
        RECT 174.640 568.700 793.940 570.300 ;
    END
    PORT
      LAYER met4 ;
        RECT 1817.580 3078.800 1819.180 3544.400 ;
    END
    PORT
      LAYER met4 ;
        RECT 2581.180 3078.800 2582.780 3544.400 ;
    END
    PORT
      LAYER met4 ;
        RECT 3343.860 3097.840 3345.460 3544.400 ;
    END
  END VPWR
  PIN anode[0]
    DIRECTION OUTPUT ;
    USE SIGNAL ;
    ANTENNADIFFAREA 0.340600 ;
    PORT
      LAYER met2 ;
        RECT 1896.210 0.000 1896.490 0.280 ;
    END
  END anode[0]
  PIN anode[1]
    DIRECTION OUTPUT ;
    USE SIGNAL ;
    ANTENNADIFFAREA 0.340600 ;
    PORT
      LAYER met2 ;
        RECT 1883.330 0.000 1883.610 0.280 ;
    END
  END anode[1]
  PIN anode[2]
    DIRECTION OUTPUT ;
    USE SIGNAL ;
    ANTENNADIFFAREA 0.340600 ;
    PORT
      LAYER met2 ;
        RECT 1890.690 0.000 1890.970 0.280 ;
    END
  END anode[2]
  PIN anode[3]
    DIRECTION OUTPUT ;
    USE SIGNAL ;
    ANTENNADIFFAREA 0.340600 ;
    PORT
      LAYER met2 ;
        RECT 1871.370 0.000 1871.650 0.280 ;
    END
  END anode[3]
  PIN anode[4]
    DIRECTION OUTPUT ;
    USE SIGNAL ;
    ANTENNADIFFAREA 0.340600 ;
    PORT
      LAYER met2 ;
        RECT 1911.850 0.000 1912.130 0.280 ;
    END
  END anode[4]
  PIN anode[5]
    DIRECTION OUTPUT ;
    USE SIGNAL ;
    ANTENNADIFFAREA 0.340600 ;
    PORT
      LAYER met2 ;
        RECT 1864.010 0.000 1864.290 0.280 ;
    END
  END anode[5]
  PIN anode[6]
    DIRECTION OUTPUT ;
    USE SIGNAL ;
    ANTENNADIFFAREA 0.340600 ;
    PORT
      LAYER met2 ;
        RECT 1867.690 0.000 1867.970 0.280 ;
    END
  END anode[6]
  PIN anode[7]
    DIRECTION OUTPUT ;
    USE SIGNAL ;
    ANTENNADIFFAREA 0.340600 ;
    PORT
      LAYER met2 ;
        RECT 1884.250 0.000 1884.530 0.280 ;
    END
  END anode[7]
  PIN catode[0]
    DIRECTION OUTPUT ;
    USE SIGNAL ;
    ANTENNADIFFAREA 0.340600 ;
    PORT
      LAYER met2 ;
        RECT 1947.730 0.000 1948.010 0.280 ;
    END
  END catode[0]
  PIN catode[1]
    DIRECTION OUTPUT ;
    USE SIGNAL ;
    ANTENNADIFFAREA 0.340600 ;
    PORT
      LAYER met2 ;
        RECT 1948.650 0.000 1948.930 0.280 ;
    END
  END catode[1]
  PIN catode[2]
    DIRECTION OUTPUT ;
    USE SIGNAL ;
    ANTENNADIFFAREA 0.340600 ;
    PORT
      LAYER met2 ;
        RECT 1919.210 0.000 1919.490 0.280 ;
    END
  END catode[2]
  PIN catode[3]
    DIRECTION OUTPUT ;
    USE SIGNAL ;
    ANTENNADIFFAREA 0.340600 ;
    PORT
      LAYER met2 ;
        RECT 1909.090 0.000 1909.370 0.280 ;
    END
  END catode[3]
  PIN catode[4]
    DIRECTION OUTPUT ;
    USE SIGNAL ;
    ANTENNADIFFAREA 0.340600 ;
    PORT
      LAYER met2 ;
        RECT 1954.170 0.000 1954.450 0.280 ;
    END
  END catode[4]
  PIN catode[5]
    DIRECTION OUTPUT ;
    USE SIGNAL ;
    ANTENNADIFFAREA 0.340600 ;
    PORT
      LAYER met2 ;
        RECT 1877.810 0.000 1878.090 0.280 ;
    END
  END catode[5]
  PIN catode[6]
    DIRECTION OUTPUT ;
    USE SIGNAL ;
    ANTENNADIFFAREA 0.340600 ;
    PORT
      LAYER met2 ;
        RECT 1858.490 0.000 1858.770 0.280 ;
    END
  END catode[6]
  PIN catode[7]
    DIRECTION OUTPUT ;
    USE SIGNAL ;
    ANTENNADIFFAREA 0.340600 ;
    PORT
      LAYER met2 ;
        RECT 1863.090 0.000 1863.370 0.280 ;
    END
  END catode[7]
  PIN clk_i
    DIRECTION INPUT ;
    USE SIGNAL ;
    ANTENNAGATEAREA 0.990000 ;
    PORT
      LAYER met2 ;
        RECT 4013.130 3599.720 4013.410 3600.000 ;
    END
  END clk_i
  PIN rst_ni
    DIRECTION INPUT ;
    USE SIGNAL ;
    ANTENNAGATEAREA 0.196500 ;
    PORT
      LAYER met2 ;
        RECT 2083.890 3599.720 2084.170 3600.000 ;
    END
  END rst_ni
  OBS
      LAYER nwell ;
        RECT 5.330 10.760 4194.470 3587.870 ;
      LAYER li1 ;
        RECT 5.520 10.795 4194.280 3587.765 ;
      LAYER met1 ;
        RECT 5.520 0.040 4194.280 3587.920 ;
      LAYER met2 ;
        RECT 21.070 3599.440 2083.610 3599.765 ;
        RECT 2084.450 3599.440 2144.330 3599.765 ;
        RECT 2145.170 3599.440 2192.170 3599.765 ;
        RECT 2193.010 3599.440 2199.530 3599.765 ;
        RECT 2200.370 3599.440 2220.690 3599.765 ;
        RECT 2221.530 3599.440 2295.210 3599.765 ;
        RECT 2296.050 3599.440 2297.050 3599.765 ;
        RECT 2297.890 3599.440 2320.050 3599.765 ;
        RECT 2320.890 3599.440 2332.930 3599.765 ;
        RECT 2333.770 3599.440 2394.570 3599.765 ;
        RECT 2395.410 3599.440 2405.610 3599.765 ;
        RECT 2406.450 3599.440 4012.850 3599.765 ;
        RECT 4013.690 3599.440 4192.810 3599.765 ;
        RECT 21.070 0.560 4192.810 3599.440 ;
        RECT 21.070 0.010 1767.130 0.560 ;
        RECT 1767.970 0.010 1826.010 0.560 ;
        RECT 1826.850 0.010 1844.410 0.560 ;
        RECT 1845.250 0.010 1858.210 0.560 ;
        RECT 1859.050 0.010 1862.810 0.560 ;
        RECT 1863.650 0.010 1863.730 0.560 ;
        RECT 1864.570 0.010 1866.490 0.560 ;
        RECT 1867.330 0.010 1867.410 0.560 ;
        RECT 1868.250 0.010 1869.250 0.560 ;
        RECT 1870.090 0.010 1870.170 0.560 ;
        RECT 1871.010 0.010 1871.090 0.560 ;
        RECT 1871.930 0.010 1873.850 0.560 ;
        RECT 1874.690 0.010 1875.690 0.560 ;
        RECT 1876.530 0.010 1877.530 0.560 ;
        RECT 1878.370 0.010 1878.450 0.560 ;
        RECT 1879.290 0.010 1879.370 0.560 ;
        RECT 1880.210 0.010 1880.290 0.560 ;
        RECT 1881.130 0.010 1881.210 0.560 ;
        RECT 1882.050 0.010 1882.130 0.560 ;
        RECT 1882.970 0.010 1883.050 0.560 ;
        RECT 1883.890 0.010 1883.970 0.560 ;
        RECT 1884.810 0.010 1884.890 0.560 ;
        RECT 1885.730 0.010 1885.810 0.560 ;
        RECT 1886.650 0.010 1886.730 0.560 ;
        RECT 1887.570 0.010 1887.650 0.560 ;
        RECT 1888.490 0.010 1888.570 0.560 ;
        RECT 1889.410 0.010 1889.490 0.560 ;
        RECT 1890.330 0.010 1890.410 0.560 ;
        RECT 1891.250 0.010 1891.330 0.560 ;
        RECT 1892.170 0.010 1892.250 0.560 ;
        RECT 1893.090 0.010 1893.170 0.560 ;
        RECT 1894.010 0.010 1895.010 0.560 ;
        RECT 1895.850 0.010 1895.930 0.560 ;
        RECT 1896.770 0.010 1896.850 0.560 ;
        RECT 1897.690 0.010 1897.770 0.560 ;
        RECT 1898.610 0.010 1898.690 0.560 ;
        RECT 1899.530 0.010 1899.610 0.560 ;
        RECT 1900.450 0.010 1900.530 0.560 ;
        RECT 1901.370 0.010 1901.450 0.560 ;
        RECT 1902.290 0.010 1902.370 0.560 ;
        RECT 1903.210 0.010 1906.970 0.560 ;
        RECT 1907.810 0.010 1908.810 0.560 ;
        RECT 1909.650 0.010 1910.650 0.560 ;
        RECT 1911.490 0.010 1911.570 0.560 ;
        RECT 1912.410 0.010 1912.490 0.560 ;
        RECT 1913.330 0.010 1913.410 0.560 ;
        RECT 1914.250 0.010 1914.330 0.560 ;
        RECT 1915.170 0.010 1915.250 0.560 ;
        RECT 1916.090 0.010 1916.170 0.560 ;
        RECT 1917.010 0.010 1917.090 0.560 ;
        RECT 1917.930 0.010 1918.930 0.560 ;
        RECT 1919.770 0.010 1920.770 0.560 ;
        RECT 1921.610 0.010 1921.690 0.560 ;
        RECT 1922.530 0.010 1941.930 0.560 ;
        RECT 1942.770 0.010 1944.690 0.560 ;
        RECT 1945.530 0.010 1945.610 0.560 ;
        RECT 1946.450 0.010 1946.530 0.560 ;
        RECT 1947.370 0.010 1947.450 0.560 ;
        RECT 1948.290 0.010 1948.370 0.560 ;
        RECT 1949.210 0.010 1949.290 0.560 ;
        RECT 1950.130 0.010 1950.210 0.560 ;
        RECT 1951.050 0.010 1951.130 0.560 ;
        RECT 1951.970 0.010 1952.050 0.560 ;
        RECT 1952.890 0.010 1953.890 0.560 ;
        RECT 1954.730 0.010 1964.010 0.560 ;
        RECT 1964.850 0.010 1964.930 0.560 ;
        RECT 1965.770 0.010 1965.850 0.560 ;
        RECT 1966.690 0.010 1966.770 0.560 ;
        RECT 1967.610 0.010 2045.890 0.560 ;
        RECT 2046.730 0.010 2105.690 0.560 ;
        RECT 2106.530 0.010 2148.930 0.560 ;
        RECT 2149.770 0.010 2156.290 0.560 ;
        RECT 2157.130 0.010 2214.250 0.560 ;
        RECT 2215.090 0.010 2238.170 0.560 ;
        RECT 2239.010 0.010 2254.730 0.560 ;
        RECT 2255.570 0.010 2255.650 0.560 ;
        RECT 2256.490 0.010 2256.570 0.560 ;
        RECT 2257.410 0.010 2435.050 0.560 ;
        RECT 2435.890 0.010 4192.810 0.560 ;
      LAYER met3 ;
        RECT 21.050 1876.480 4199.400 3599.745 ;
        RECT 21.050 1875.080 4199.000 1876.480 ;
        RECT 21.050 1832.960 4199.400 1875.080 ;
        RECT 21.050 1831.560 4199.000 1832.960 ;
        RECT 21.050 1782.640 4199.400 1831.560 ;
        RECT 21.050 1781.240 4199.000 1782.640 ;
        RECT 21.050 1680.640 4199.400 1781.240 ;
        RECT 21.050 1679.240 4199.000 1680.640 ;
        RECT 21.050 6.975 4199.400 1679.240 ;
      LAYER met4 ;
        RECT 38.935 2642.020 174.240 3575.265 ;
        RECT 176.640 2642.020 177.540 3575.265 ;
        RECT 179.940 3529.280 327.840 3575.265 ;
        RECT 330.240 3529.280 331.140 3575.265 ;
        RECT 333.540 3529.280 481.440 3575.265 ;
        RECT 483.840 3529.280 484.740 3575.265 ;
        RECT 487.140 3529.280 635.040 3575.265 ;
        RECT 637.440 3530.200 638.340 3575.265 ;
        RECT 640.740 3530.200 788.640 3575.265 ;
        RECT 791.040 3530.200 791.940 3575.265 ;
        RECT 637.440 3529.280 791.940 3530.200 ;
        RECT 794.340 3529.280 942.240 3575.265 ;
        RECT 944.640 3529.280 945.540 3575.265 ;
        RECT 947.940 3544.800 1095.840 3575.265 ;
        RECT 947.940 3529.280 1054.500 3544.800 ;
        RECT 179.940 3094.180 1054.500 3529.280 ;
        RECT 179.940 2642.020 327.840 3094.180 ;
        RECT 330.240 2642.020 331.140 3094.180 ;
        RECT 333.540 2642.020 481.440 3094.180 ;
        RECT 483.840 3093.260 635.040 3094.180 ;
        RECT 483.840 2642.940 484.740 3093.260 ;
        RECT 487.140 2642.940 635.040 3093.260 ;
        RECT 483.840 2642.020 635.040 2642.940 ;
        RECT 637.440 3093.260 791.940 3094.180 ;
        RECT 637.440 2642.020 638.340 3093.260 ;
        RECT 640.740 2642.020 788.640 3093.260 ;
        RECT 38.935 2206.920 788.640 2642.020 ;
        RECT 38.935 1858.920 174.240 2206.920 ;
        RECT 176.640 2206.000 331.140 2206.920 ;
        RECT 176.640 1858.920 177.540 2206.000 ;
        RECT 179.940 1858.920 327.840 2206.000 ;
        RECT 330.240 1858.920 331.140 2206.000 ;
        RECT 333.540 1858.920 481.440 2206.920 ;
        RECT 483.840 2206.000 635.040 2206.920 ;
        RECT 483.840 1859.840 484.740 2206.000 ;
        RECT 487.140 1859.840 635.040 2206.000 ;
        RECT 483.840 1858.920 635.040 1859.840 ;
        RECT 637.440 1858.920 638.340 2206.920 ;
        RECT 640.740 1858.920 788.640 2206.920 ;
        RECT 38.935 1423.820 788.640 1858.920 ;
        RECT 38.935 1075.820 174.240 1423.820 ;
        RECT 176.640 1422.900 331.140 1423.820 ;
        RECT 176.640 1075.820 177.540 1422.900 ;
        RECT 179.940 1075.820 327.840 1422.900 ;
        RECT 330.240 1075.820 331.140 1422.900 ;
        RECT 333.540 1075.820 481.440 1423.820 ;
        RECT 483.840 1422.900 635.040 1423.820 ;
        RECT 483.840 1076.740 484.740 1422.900 ;
        RECT 487.140 1076.740 635.040 1422.900 ;
        RECT 483.840 1075.820 635.040 1076.740 ;
        RECT 637.440 1075.820 638.340 1423.820 ;
        RECT 640.740 1075.820 788.640 1423.820 ;
        RECT 38.935 640.720 788.640 1075.820 ;
        RECT 38.935 12.415 174.240 640.720 ;
        RECT 176.640 639.800 331.140 640.720 ;
        RECT 176.640 12.415 177.540 639.800 ;
        RECT 179.940 505.820 327.840 639.800 ;
        RECT 330.240 505.820 331.140 639.800 ;
        RECT 333.540 505.820 481.440 640.720 ;
        RECT 483.840 639.800 635.040 640.720 ;
        RECT 483.840 505.820 484.740 639.800 ;
        RECT 487.140 506.740 635.040 639.800 ;
        RECT 637.440 506.740 638.340 640.720 ;
        RECT 487.140 505.820 638.340 506.740 ;
        RECT 640.740 505.820 788.640 640.720 ;
        RECT 791.040 505.820 791.940 3093.260 ;
        RECT 794.340 505.820 942.240 3094.180 ;
        RECT 179.940 70.720 942.240 505.820 ;
        RECT 179.940 69.800 331.140 70.720 ;
        RECT 179.940 12.415 327.840 69.800 ;
        RECT 330.240 12.415 331.140 69.800 ;
        RECT 333.540 69.800 638.340 70.720 ;
        RECT 333.540 12.415 481.440 69.800 ;
        RECT 483.840 12.415 484.740 69.800 ;
        RECT 487.140 12.415 635.040 69.800 ;
        RECT 637.440 12.415 638.340 69.800 ;
        RECT 640.740 12.415 788.640 70.720 ;
        RECT 791.040 12.415 791.940 70.720 ;
        RECT 794.340 12.415 942.240 70.720 ;
        RECT 944.640 12.415 945.540 3094.180 ;
        RECT 947.940 3078.400 1054.500 3094.180 ;
        RECT 1056.900 3078.400 1058.180 3544.800 ;
        RECT 1060.580 3529.280 1095.840 3544.800 ;
        RECT 1098.240 3529.280 1099.140 3575.265 ;
        RECT 1101.540 3529.280 1249.440 3575.265 ;
        RECT 1251.840 3529.280 1252.740 3575.265 ;
        RECT 1255.140 3529.280 1403.040 3575.265 ;
        RECT 1405.440 3529.280 1406.340 3575.265 ;
        RECT 1408.740 3529.280 1556.640 3575.265 ;
        RECT 1559.040 3529.280 1559.940 3575.265 ;
        RECT 1562.340 3529.280 1710.240 3575.265 ;
        RECT 1712.640 3529.280 1713.540 3575.265 ;
        RECT 1715.940 3544.800 1863.840 3575.265 ;
        RECT 1715.940 3529.280 1817.180 3544.800 ;
        RECT 1060.580 3094.180 1817.180 3529.280 ;
        RECT 1060.580 3078.400 1095.840 3094.180 ;
        RECT 947.940 505.820 1095.840 3078.400 ;
        RECT 1098.240 505.820 1099.140 3094.180 ;
        RECT 1101.540 3093.260 1403.040 3094.180 ;
        RECT 1101.540 506.740 1249.440 3093.260 ;
        RECT 1251.840 506.740 1252.740 3093.260 ;
        RECT 1101.540 505.820 1252.740 506.740 ;
        RECT 1255.140 505.820 1403.040 3093.260 ;
        RECT 1405.440 505.820 1406.340 3094.180 ;
        RECT 1408.740 505.820 1556.640 3094.180 ;
        RECT 1559.040 505.820 1559.940 3094.180 ;
        RECT 1562.340 505.820 1710.240 3094.180 ;
        RECT 947.940 70.720 1710.240 505.820 ;
        RECT 947.940 69.800 1099.140 70.720 ;
        RECT 947.940 12.415 1095.840 69.800 ;
        RECT 1098.240 12.415 1099.140 69.800 ;
        RECT 1101.540 69.800 1252.740 70.720 ;
        RECT 1101.540 12.415 1249.440 69.800 ;
        RECT 1251.840 12.415 1252.740 69.800 ;
        RECT 1255.140 12.415 1403.040 70.720 ;
        RECT 1405.440 12.415 1406.340 70.720 ;
        RECT 1408.740 12.415 1556.640 70.720 ;
        RECT 1559.040 12.415 1559.940 70.720 ;
        RECT 1562.340 12.415 1710.240 70.720 ;
        RECT 1712.640 3093.260 1817.180 3094.180 ;
        RECT 1712.640 12.415 1713.540 3093.260 ;
        RECT 1715.940 3078.400 1817.180 3093.260 ;
        RECT 1819.580 3078.400 1820.860 3544.800 ;
        RECT 1823.260 3529.280 1863.840 3544.800 ;
        RECT 1866.240 3529.280 1867.140 3575.265 ;
        RECT 1869.540 3529.280 2017.440 3575.265 ;
        RECT 2019.840 3529.280 2020.740 3575.265 ;
        RECT 2023.140 3529.280 2171.040 3575.265 ;
        RECT 2173.440 3529.280 2174.340 3575.265 ;
        RECT 2176.740 3529.280 2324.640 3575.265 ;
        RECT 2327.040 3530.200 2327.940 3575.265 ;
        RECT 2330.340 3530.200 2478.240 3575.265 ;
        RECT 2327.040 3529.280 2478.240 3530.200 ;
        RECT 2480.640 3529.280 2481.540 3575.265 ;
        RECT 2483.940 3544.800 2631.840 3575.265 ;
        RECT 2483.940 3529.280 2580.780 3544.800 ;
        RECT 1823.260 3094.180 2580.780 3529.280 ;
        RECT 1823.260 3078.400 1863.840 3094.180 ;
        RECT 1715.940 505.820 1863.840 3078.400 ;
        RECT 1866.240 505.820 1867.140 3094.180 ;
        RECT 1869.540 505.820 2017.440 3094.180 ;
        RECT 2019.840 3093.260 2171.040 3094.180 ;
        RECT 2019.840 505.820 2020.740 3093.260 ;
        RECT 2023.140 505.820 2171.040 3093.260 ;
        RECT 2173.440 506.740 2174.340 3094.180 ;
        RECT 2176.740 506.740 2324.640 3094.180 ;
        RECT 2173.440 505.820 2324.640 506.740 ;
        RECT 2327.040 505.820 2327.940 3094.180 ;
        RECT 2330.340 505.820 2478.240 3094.180 ;
        RECT 1715.940 70.720 2478.240 505.820 ;
        RECT 1715.940 12.415 1863.840 70.720 ;
        RECT 1866.240 69.800 2020.740 70.720 ;
        RECT 1866.240 12.415 1867.140 69.800 ;
        RECT 1869.540 12.415 2017.440 69.800 ;
        RECT 2019.840 12.415 2020.740 69.800 ;
        RECT 2023.140 12.415 2171.040 70.720 ;
        RECT 2173.440 69.800 2324.640 70.720 ;
        RECT 2173.440 12.415 2174.340 69.800 ;
        RECT 2176.740 12.415 2324.640 69.800 ;
        RECT 2327.040 12.415 2327.940 70.720 ;
        RECT 2330.340 12.415 2478.240 70.720 ;
        RECT 2480.640 12.415 2481.540 3094.180 ;
        RECT 2483.940 3078.400 2580.780 3094.180 ;
        RECT 2583.180 3078.400 2584.460 3544.800 ;
        RECT 2586.860 3529.280 2631.840 3544.800 ;
        RECT 2634.240 3529.280 2635.140 3575.265 ;
        RECT 2637.540 3529.280 2785.440 3575.265 ;
        RECT 2787.840 3530.200 2788.740 3575.265 ;
        RECT 2791.140 3530.200 2939.040 3575.265 ;
        RECT 2941.440 3530.200 2942.340 3575.265 ;
        RECT 2787.840 3529.280 2942.340 3530.200 ;
        RECT 2944.740 3529.280 3092.640 3575.265 ;
        RECT 3095.040 3529.280 3095.940 3575.265 ;
        RECT 3098.340 3529.280 3246.240 3575.265 ;
        RECT 3248.640 3529.280 3249.540 3575.265 ;
        RECT 3251.940 3544.800 3399.840 3575.265 ;
        RECT 3251.940 3529.280 3343.460 3544.800 ;
        RECT 2586.860 3097.440 3343.460 3529.280 ;
        RECT 3345.860 3097.440 3347.140 3544.800 ;
        RECT 3349.540 3529.280 3399.840 3544.800 ;
        RECT 3402.240 3529.280 3403.140 3575.265 ;
        RECT 3405.540 3529.280 3553.440 3575.265 ;
        RECT 3555.840 3530.200 3556.740 3575.265 ;
        RECT 3559.140 3530.200 3707.040 3575.265 ;
        RECT 3709.440 3530.200 3710.340 3575.265 ;
        RECT 3555.840 3529.280 3710.340 3530.200 ;
        RECT 3712.740 3529.280 3860.640 3575.265 ;
        RECT 3863.040 3529.280 3863.940 3575.265 ;
        RECT 3866.340 3529.280 4014.240 3575.265 ;
        RECT 3349.540 3113.220 4014.240 3529.280 ;
        RECT 3349.540 3097.440 3399.840 3113.220 ;
        RECT 2586.860 3094.180 3399.840 3097.440 ;
        RECT 2586.860 3078.400 2631.840 3094.180 ;
        RECT 2483.940 505.820 2631.840 3078.400 ;
        RECT 2634.240 505.820 2635.140 3094.180 ;
        RECT 2637.540 3093.260 2942.340 3094.180 ;
        RECT 2637.540 505.820 2785.440 3093.260 ;
        RECT 2787.840 506.740 2788.740 3093.260 ;
        RECT 2791.140 506.740 2939.040 3093.260 ;
        RECT 2941.440 506.740 2942.340 3093.260 ;
        RECT 2787.840 505.820 2942.340 506.740 ;
        RECT 2944.740 505.820 3092.640 3094.180 ;
        RECT 3095.040 505.820 3095.940 3094.180 ;
        RECT 3098.340 505.820 3246.240 3094.180 ;
        RECT 2483.940 70.720 3246.240 505.820 ;
        RECT 2483.940 12.415 2631.840 70.720 ;
        RECT 2634.240 69.800 2785.440 70.720 ;
        RECT 2634.240 12.415 2635.140 69.800 ;
        RECT 2637.540 12.415 2785.440 69.800 ;
        RECT 2787.840 69.800 2942.340 70.720 ;
        RECT 2787.840 12.415 2788.740 69.800 ;
        RECT 2791.140 12.415 2939.040 69.800 ;
        RECT 2941.440 12.415 2942.340 69.800 ;
        RECT 2944.740 12.415 3092.640 70.720 ;
        RECT 3095.040 12.415 3095.940 70.720 ;
        RECT 3098.340 12.415 3246.240 70.720 ;
        RECT 3248.640 12.415 3249.540 3094.180 ;
        RECT 3251.940 505.820 3399.840 3094.180 ;
        RECT 3402.240 505.820 3403.140 3113.220 ;
        RECT 3405.540 2375.820 3553.440 3113.220 ;
        RECT 3555.840 3112.300 3710.340 3113.220 ;
        RECT 3555.840 2375.820 3556.740 3112.300 ;
        RECT 3559.140 2375.820 3707.040 3112.300 ;
        RECT 3709.440 2375.820 3710.340 3112.300 ;
        RECT 3712.740 2375.820 3860.640 3113.220 ;
        RECT 3863.040 2375.820 3863.940 3113.220 ;
        RECT 3866.340 2375.820 4014.240 3113.220 ;
        RECT 4016.640 2375.820 4017.540 3575.265 ;
        RECT 4019.940 2375.820 4146.145 3575.265 ;
        RECT 3405.540 1940.720 4146.145 2375.820 ;
        RECT 3405.540 1475.820 3553.440 1940.720 ;
        RECT 3555.840 1939.800 3710.340 1940.720 ;
        RECT 3555.840 1475.820 3556.740 1939.800 ;
        RECT 3559.140 1475.820 3707.040 1939.800 ;
        RECT 3709.440 1475.820 3710.340 1939.800 ;
        RECT 3712.740 1475.820 3860.640 1940.720 ;
        RECT 3863.040 1475.820 3863.940 1940.720 ;
        RECT 3866.340 1475.820 4014.240 1940.720 ;
        RECT 4016.640 1475.820 4017.540 1940.720 ;
        RECT 4019.940 1475.820 4146.145 1940.720 ;
        RECT 3405.540 1040.720 4146.145 1475.820 ;
        RECT 3405.540 505.820 3553.440 1040.720 ;
        RECT 3555.840 1039.800 3710.340 1040.720 ;
        RECT 3555.840 505.820 3556.740 1039.800 ;
        RECT 3559.140 505.820 3707.040 1039.800 ;
        RECT 3709.440 505.820 3710.340 1039.800 ;
        RECT 3712.740 505.820 3860.640 1040.720 ;
        RECT 3863.040 505.820 3863.940 1040.720 ;
        RECT 3866.340 505.820 4014.240 1040.720 ;
        RECT 3251.940 70.720 4014.240 505.820 ;
        RECT 3251.940 69.800 3553.440 70.720 ;
        RECT 3251.940 12.415 3399.840 69.800 ;
        RECT 3402.240 12.415 3403.140 69.800 ;
        RECT 3405.540 12.415 3553.440 69.800 ;
        RECT 3555.840 69.800 3707.040 70.720 ;
        RECT 3555.840 12.415 3556.740 69.800 ;
        RECT 3559.140 12.415 3707.040 69.800 ;
        RECT 3709.440 12.415 3710.340 70.720 ;
        RECT 3712.740 12.415 3860.640 70.720 ;
        RECT 3863.040 12.415 3863.940 70.720 ;
        RECT 3866.340 12.415 4014.240 70.720 ;
        RECT 4016.640 12.415 4017.540 1040.720 ;
        RECT 4019.940 12.415 4146.145 1040.720 ;
  END
END top_module
END LIBRARY

